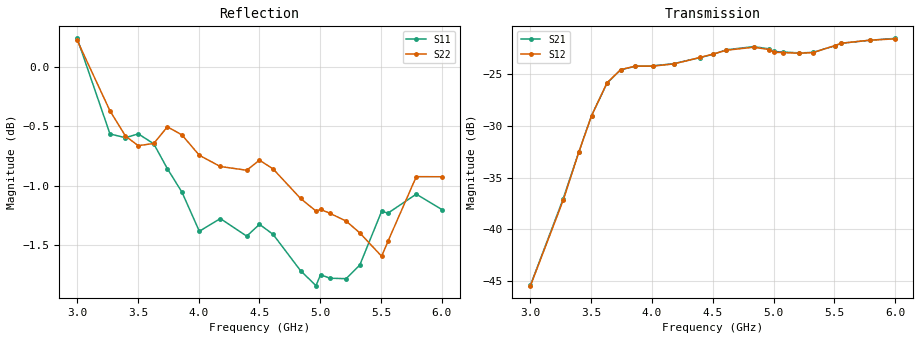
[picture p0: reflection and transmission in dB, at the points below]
!  26/11/2025  14:48:31
! Ref Plane: 0.000 mm
# MHZ S MA R  50
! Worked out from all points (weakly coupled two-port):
!   401 points, 3 GHz to 6 GHz, reference 50 ohm
!   highest |S21| = -21.50 dB at 6 GHz (marker M1); lowest = -45.5 dB at 3 GHz (marker M2)
!   lowest |S11| = -1.8 dB at 4.965 GHz (marker M3), VSWR 9.46, Z = 11.6 - j54 ohm
!   |S11| at or under -10 dB: nowhere
!   |S22| runs from -1.7 to 0.3 dB; largest |S21 - S12| = 0.0036
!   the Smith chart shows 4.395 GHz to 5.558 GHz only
!   S11 on the Smith chart (normalised r, x): 4.395 GHz: 0.15, +0.89; 4.612 GHz: 1.40, +3.80; 4.838 GHz: 0.65, -2.29; 5.077 GHz: 0.14, -0.60; 5.325 GHz: 0.10, +0.07; 5.558 GHz: 0.11, +0.77
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3000  1.028 -138.8  0.005337 48.7  0.00531 50.7  1.026 -106.4
3270  0.937 151.5  0.01406 -18.1  0.01383 -15.5  0.9582 -171.7
3397.5  0.9336 108.3  0.0236 -58.4  0.02358 -57.0  0.9351 149.7
3502.5  0.9371 65.5  0.03551 -98.9  0.03545 -97.6  0.9264 111.7
3630  0.9281 10.9  0.05103 -154.8  0.05123 -153.4  0.9284 56.3
3742.5  0.9059 -37.9  0.05931 155.4  0.05932 157.1  0.9435 7.2
3862.5  0.8855 -84.9  0.06156 106.7  0.06177 108.3  0.9361 -42.1
4005  0.8526 -136.7  0.06192 56.0  0.06171 57.3  0.9178 -92.1
4177.5  0.8632 166.5  0.06342 0.3  0.06325 2.2  0.9079 -145.7
4395  0.8486 95.9  0.06789 -67.3  0.068 -65.5  0.9046 149.8
4500  0.8584 62.9  0.07035 -98.8  0.07057 -97.2  0.9135 117.0
4612.5  0.85 26.2  0.07409 -133.9  0.07373 -132.8  0.9057 80.5
4837.5  0.8207 -44.5  0.07678 154.7  0.07624 156.3  0.8802 11.6
4965  0.8088 -84.2  0.07477 117.0  0.07421 118.6  0.8695 -24.9
5002.5  0.8175 -95.9  0.0727 106.5  0.07209 107.8  0.8709 -36.3
5077.5  0.8147 -117.5  0.07226 85.7  0.07177 87.0  0.8677 -56.6
5212.5  0.8143 -156.6  0.07157 48.9  0.07128 50.1  0.8611 -93.6
5325  0.8251 172.5  0.07195 18.5  0.07181 20.1  0.8513 -127.7
5505  0.8693 120.2  0.07754 -31.4  0.07763 -29.2  0.8322 -176.6
5557.5  0.8678 104.5  0.0797 -46.5  0.07971 -44.1  0.8445 170.8
5790  0.8839 40.5  0.08239 -113.1  0.08245 -110.9  0.899 103.5
6000  0.8708 -20.2  0.08417 -173.3  0.08373 -171.7  0.8989 48.9
